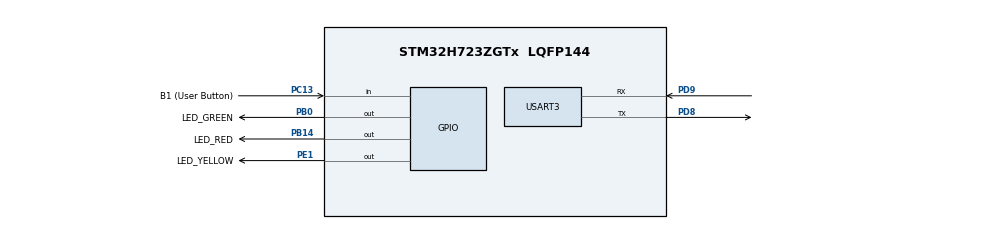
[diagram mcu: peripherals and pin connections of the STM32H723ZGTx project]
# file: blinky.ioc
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CORTEX_M7.default_mode_Activation=1
Mcu.Family=STM32H7
Mcu.Name=STM32H723ZGTx
Mcu.Package=LQFP144
NVIC.PriorityGroup=NVIC_PRIORITYGROUP_4
PA13(JTMS/SWDIO).GPIO_Label=SWDIO
PA13(JTMS/SWDIO).Signal=DEBUG_JTMS-SWDIO
PA14(JTCK/SWCLK).GPIO_Label=SWCLK
PA14(JTCK/SWCLK).Signal=DEBUG_JTCK-SWCLK
PB0.GPIO_Label=LED_GREEN
PB0.Signal=GPIO_Output
PB14.GPIO_Label=LED_RED
PB14.Signal=GPIO_Output
PC13.GPIO_Label=B1 (User Button)
PC13.Signal=GPIO_Input
PC14-OSC32_IN.Signal=RCC_OSC32_IN
PC15-OSC32_OUT.Signal=RCC_OSC32_OUT
PD8.Mode=Asynchronous
PD8.Signal=USART3_TX
PD9.Mode=Asynchronous
PD9.Signal=USART3_RX
PE1.GPIO_Label=LED_YELLOW
PE1.Signal=GPIO_Output
ProjectManager.HeapSize=0x200
ProjectManager.StackSize=0x400
ProjectManager.TargetToolchain=STM32CubeIDE
RCC.ADCFreq_Value=608000000
RCC.APB1Freq_Value=137500000
RCC.APB2Freq_Value=137500000
RCC.APB3Freq_Value=137500000
RCC.APB4Freq_Value=137500000
RCC.CortexFreq_Value=550000000
RCC.D1PPRE=RCC_APB3_DIV2
RCC.D2PPRE1=RCC_APB1_DIV2
RCC.D2PPRE2=RCC_APB2_DIV2
RCC.D3PPRE=RCC_APB4_DIV2
RCC.DIVM1=4
RCC.DIVM2=1
RCC.DIVN1=34
RCC.DIVN2=19
RCC.DIVP1=1
RCC.DIVQ1=4
RCC.HCLKFreq_Value=275000000
RCC.HPRE=RCC_HCLK_DIV2
RCC.HSE_VALUE=8000000
RCC.PLLFRACN=3072
RCC.SYSCLKFreq_VALUE=550000000
RCC.SYSCLKSource=RCC_SYSCLKSOURCE_PLLCLK
RCC.USBCLockSelection=RCC_USBCLKSOURCE_HSI48
RCC.USBFreq_Value=48000000
USART3.VirtualMode-Asynchronous=VM_ASYNC
VP_MEMORYMAP_VS_MEMORYMAP.Mode=CurAppReg
board=NUCLEO-H723ZG

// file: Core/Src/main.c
/* USER CODE BEGIN Header */
/**
  ******************************************************************************
  * @file           : main.c
  * @brief          : Main program body
  ******************************************************************************
  * @attention
  *
  * Copyright (c) 2025 STMicroelectronics.
  * All rights reserved.
  *
  * This software is licensed under terms that can be found in the LICENSE file
  * in the root directory of this software component.
  * If no LICENSE file comes with this software, it is provided AS-IS.
  *
  ******************************************************************************
  */
/* USER CODE END Header */
#include "main.h"

UART_HandleTypeDef huart3;

void SystemClock_Config(void);
static void MPU_Config(void);
static void MX_GPIO_Init(void);
static void MX_USART3_UART_Init(void);

int main(void)
{

  /* MPU Configuration--------------------------------------------------------*/
  MPU_Config();

  /* MCU Configuration--------------------------------------------------------*/

  /* Reset of all peripherals, Initializes the Flash interface and the Systick. */
  HAL_Init();

  /* Configure the system clock */
  SystemClock_Config();

  /* Initialize all configured peripherals */
  MX_GPIO_Init();
  MX_USART3_UART_Init();

  /* Infinite loop */
  /* USER CODE BEGIN WHILE */
  while (1)
  {
	  HAL_GPIO_WritePin(LED_GREEN_GPIO_Port, LED_GREEN_Pin, 1);
	  HAL_Delay(500);
	  HAL_GPIO_WritePin(LED_GREEN_GPIO_Port, LED_GREEN_Pin, 0);
	  HAL_Delay(500);
    /* USER CODE END WHILE */

  }
}

void SystemClock_Config(void)
{
  RCC_OscInitTypeDef RCC_OscInitStruct = {0};
  RCC_ClkInitTypeDef RCC_ClkInitStruct = {0};

  /** Supply configuration update enable
  */
  HAL_PWREx_ConfigSupply(PWR_LDO_SUPPLY);

  /** Configure the main internal regulator output voltage
  */
  __HAL_PWR_VOLTAGESCALING_CONFIG(PWR_REGULATOR_VOLTAGE_SCALE2);

  while(!__HAL_PWR_GET_FLAG(PWR_FLAG_VOSRDY)) {}

  /** Initializes the RCC Oscillators according to the specified parameters
  * in the RCC_OscInitTypeDef structure.
  */
  RCC_OscInitStruct.OscillatorType = RCC_OSCILLATORTYPE_HSI;
  RCC_OscInitStruct.HSIState = RCC_HSI_DIV1;
  RCC_OscInitStruct.HSICalibrationValue = 64;
  RCC_OscInitStruct.PLL.PLLState = RCC_PLL_ON;
  RCC_OscInitStruct.PLL.PLLSource = RCC_PLLSOURCE_HSI;
  RCC_OscInitStruct.PLL.PLLM = 4;
  RCC_OscInitStruct.PLL.PLLN = 12;
  RCC_OscInitStruct.PLL.PLLP = 1;
  RCC_OscInitStruct.PLL.PLLQ = 4;
  RCC_OscInitStruct.PLL.PLLR = 2;
  RCC_OscInitStruct.PLL.PLLRGE = RCC_PLL1VCIRANGE_3;
  RCC_OscInitStruct.PLL.PLLVCOSEL = RCC_PLL1VCOWIDE;
  RCC_OscInitStruct.PLL.PLLFRACN = 0;
  if (HAL_RCC_OscConfig(&RCC_OscInitStruct) != HAL_OK)
  {
    Error_Handler();
  }

  /** Initializes the CPU, AHB and APB buses clocks
  */
  RCC_ClkInitStruct.ClockType = RCC_CLOCKTYPE_HCLK|RCC_CLOCKTYPE_SYSCLK
                              |RCC_CLOCKTYPE_PCLK1|RCC_CLOCKTYPE_PCLK2
                              |RCC_CLOCKTYPE_D3PCLK1|RCC_CLOCKTYPE_D1PCLK1;
  RCC_ClkInitStruct.SYSCLKSource = RCC_SYSCLKSOURCE_PLLCLK;
  RCC_ClkInitStruct.SYSCLKDivider = RCC_SYSCLK_DIV1;
  RCC_ClkInitStruct.AHBCLKDivider = RCC_HCLK_DIV2;
  RCC_ClkInitStruct.APB3CLKDivider = RCC_APB3_DIV2;
  RCC_ClkInitStruct.APB1CLKDivider = RCC_APB1_DIV2;
  RCC_ClkInitStruct.APB2CLKDivider = RCC_APB2_DIV2;
  RCC_ClkInitStruct.APB4CLKDivider = RCC_APB4_DIV2;

  if (HAL_RCC_ClockConfig(&RCC_ClkInitStruct, FLASH_LATENCY_1) != HAL_OK)
  {
    Error_Handler();
  }
}

static void MX_USART3_UART_Init(void)
{

  huart3.Instance = USART3;
  huart3.Init.BaudRate = 115200;
  huart3.Init.WordLength = UART_WORDLENGTH_8B;
  huart3.Init.StopBits = UART_STOPBITS_1;
  huart3.Init.Parity = UART_PARITY_NONE;
  huart3.Init.Mode = UART_MODE_TX_RX;
  huart3.Init.HwFlowCtl = UART_HWCONTROL_NONE;
  huart3.Init.OverSampling = UART_OVERSAMPLING_16;
  huart3.Init.OneBitSampling = UART_ONE_BIT_SAMPLE_DISABLE;
  huart3.Init.ClockPrescaler = UART_PRESCALER_DIV1;
  huart3.AdvancedInit.AdvFeatureInit = UART_ADVFEATURE_NO_INIT;
  if (HAL_UART_Init(&huart3) != HAL_OK)
  {
    Error_Handler();
  }
  if (HAL_UARTEx_SetTxFifoThreshold(&huart3, UART_TXFIFO_THRESHOLD_1_8) != HAL_OK)
  {
    Error_Handler();
  }
  if (HAL_UARTEx_SetRxFifoThreshold(&huart3, UART_RXFIFO_THRESHOLD_1_8) != HAL_OK)
  {
    Error_Handler();
  }
  if (HAL_UARTEx_DisableFifoMode(&huart3) != HAL_OK)
  {
    Error_Handler();
  }

}

static void MX_GPIO_Init(void)
{
  GPIO_InitTypeDef GPIO_InitStruct = {0};

  /* GPIO Ports Clock Enable */
  __HAL_RCC_GPIOC_CLK_ENABLE();
  __HAL_RCC_GPIOB_CLK_ENABLE();
  __HAL_RCC_GPIOD_CLK_ENABLE();
  __HAL_RCC_GPIOA_CLK_ENABLE();
  __HAL_RCC_GPIOE_CLK_ENABLE();

  /*Configure GPIO pin Output Level */
  HAL_GPIO_WritePin(GPIOB, LED_GREEN_Pin|LED_RED_Pin, GPIO_PIN_RESET);

  /*Configure GPIO pin Output Level */
  HAL_GPIO_WritePin(LED_YELLOW_GPIO_Port, LED_YELLOW_Pin, GPIO_PIN_RESET);

  /*Configure GPIO pin : B1_Pin */
  GPIO_InitStruct.Pin = B1_Pin;
  GPIO_InitStruct.Mode = GPIO_MODE_INPUT;
  GPIO_InitStruct.Pull = GPIO_NOPULL;
  HAL_GPIO_Init(B1_GPIO_Port, &GPIO_InitStruct);

  /*Configure GPIO pins : LED_GREEN_Pin LED_RED_Pin */
  GPIO_InitStruct.Pin = LED_GREEN_Pin|LED_RED_Pin;
  GPIO_InitStruct.Mode = GPIO_MODE_OUTPUT_PP;
  GPIO_InitStruct.Pull = GPIO_NOPULL;
  GPIO_InitStruct.Speed = GPIO_SPEED_FREQ_LOW;
  HAL_GPIO_Init(GPIOB, &GPIO_InitStruct);

  /*Configure GPIO pin : LED_YELLOW_Pin */
  GPIO_InitStruct.Pin = LED_YELLOW_Pin;
  GPIO_InitStruct.Mode = GPIO_MODE_OUTPUT_PP;
  GPIO_InitStruct.Pull = GPIO_NOPULL;
  GPIO_InitStruct.Speed = GPIO_SPEED_FREQ_LOW;
  HAL_GPIO_Init(LED_YELLOW_GPIO_Port, &GPIO_InitStruct);

}

 /* MPU Configuration */

void MPU_Config(void)
{
  MPU_Region_InitTypeDef MPU_InitStruct = {0};

  /* Disables the MPU */
  HAL_MPU_Disable();

  /** Initializes and configures the Region and the memory to be protected
  */
  MPU_InitStruct.Enable = MPU_REGION_ENABLE;
  MPU_InitStruct.Number = MPU_REGION_NUMBER0;
  MPU_InitStruct.BaseAddress = 0x0;
  MPU_InitStruct.Size = MPU_REGION_SIZE_4GB;
  MPU_InitStruct.SubRegionDisable = 0x87;
  MPU_InitStruct.TypeExtField = MPU_TEX_LEVEL0;
  MPU_InitStruct.AccessPermission = MPU_REGION_NO_ACCESS;
  MPU_InitStruct.DisableExec = MPU_INSTRUCTION_ACCESS_DISABLE;
  MPU_InitStruct.IsShareable = MPU_ACCESS_SHAREABLE;
  MPU_InitStruct.IsCacheable = MPU_ACCESS_NOT_CACHEABLE;
  MPU_InitStruct.IsBufferable = MPU_ACCESS_NOT_BUFFERABLE;

  HAL_MPU_ConfigRegion(&MPU_InitStruct);
  /* Enables the MPU */
  HAL_MPU_Enable(MPU_PRIVILEGED_DEFAULT);

}

void Error_Handler(void)
{
  __disable_irq();
  while (1)
  {
  }
}
